(* Logix 5000 AddOnInstructionDefinition export Banner_TLF100_Param_v4; software revision 32.00; part 2 of 2 *)
(* tags used below, declared in another part *)
   TLF100 : Banner_TLF100_v2;
   Port_Data : Banner_IOL_Port_v4;
   Port : INT;   // Port Number that device is plugged into.
   Local_Control : DINT;
   Command_Being_Processed : BOOL;
   Update_Archive : BOOL;
   Index_Write_Inprocess : DINT;
   Index_Write_Control : DINT;
   Inprocess_Index : DINT;
   BS_Index : DINT;
   Index_W : DINT;
   W_Index : DINT;
   LT_Index2 : DINT;
   LT_Index1 : DINT;
(* Banner_TLF100_Param_v4, continued *)

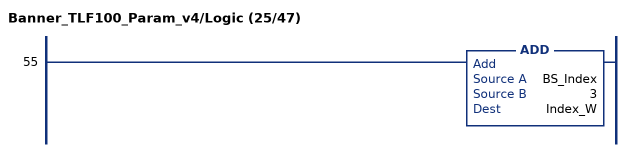
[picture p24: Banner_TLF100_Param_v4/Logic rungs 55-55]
   55: ADD(BS_Index,3,Index_W);
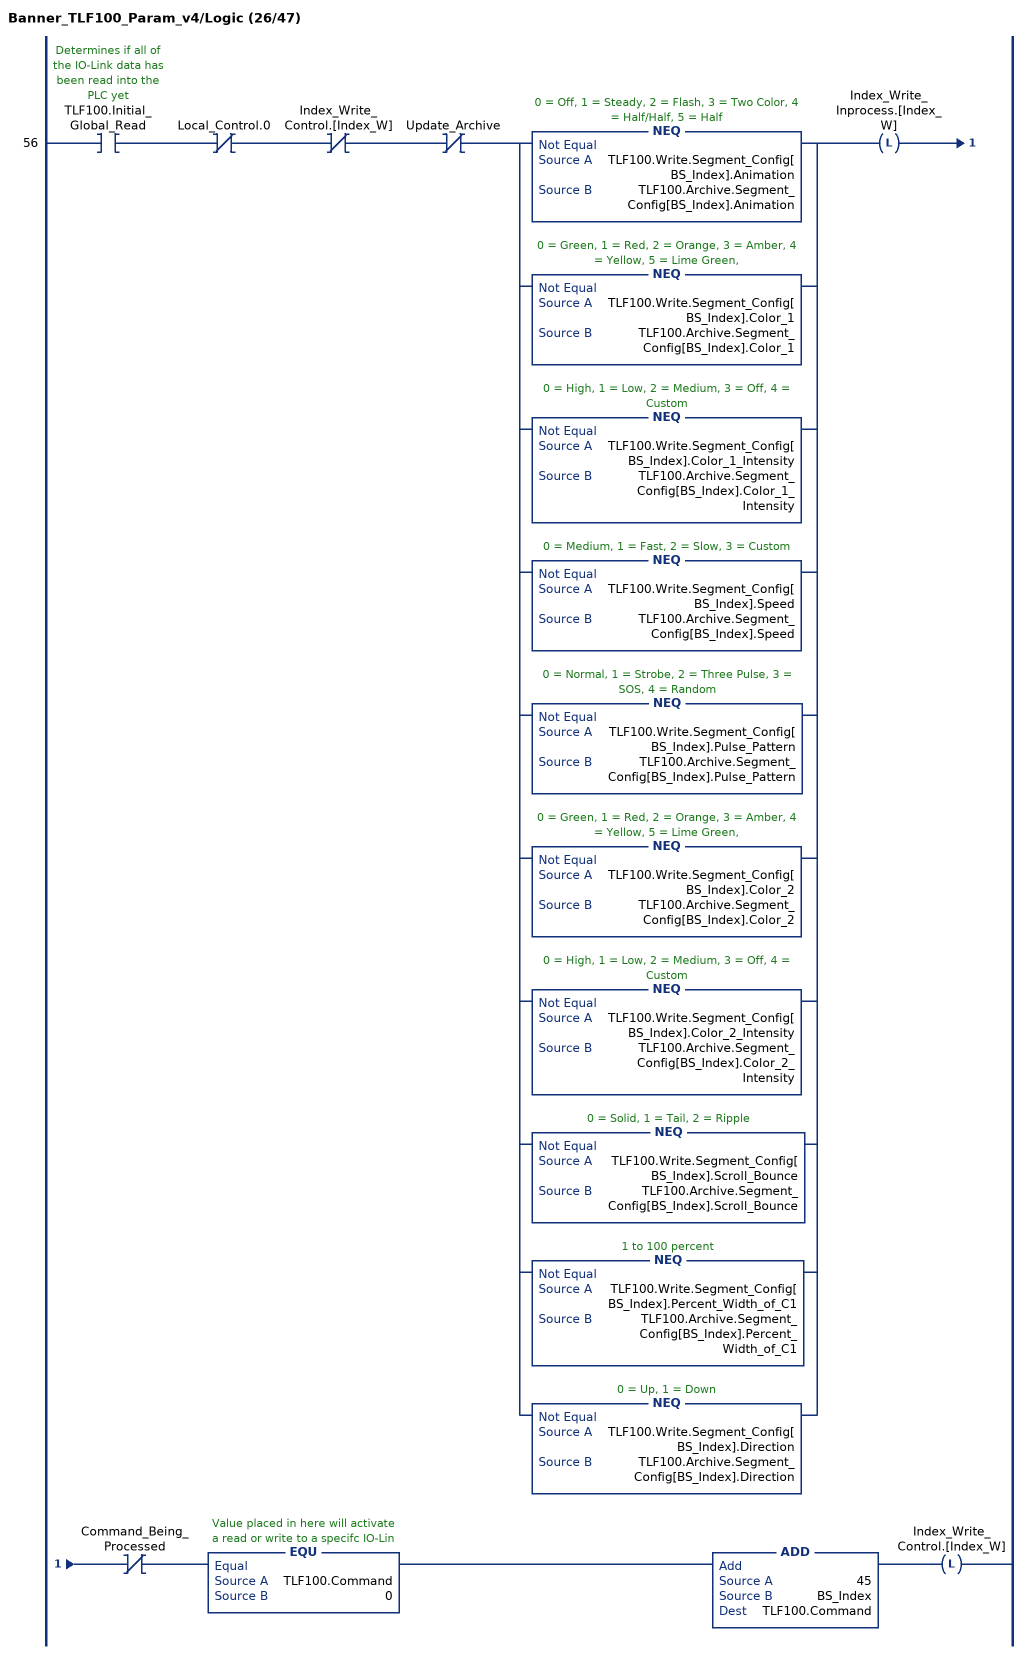
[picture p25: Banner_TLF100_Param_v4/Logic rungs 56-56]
   56: XIC(TLF100.Initial_Global_Read)XIO(Local_Control.0)XIO(Index_Write_Control.[Index_W])XIO(Update_Archive)[NEQ(TLF100.Write.Segment_Config[BS_Index].Animation,TLF100.Archive.Segment_Config[BS_Index].Animation) ,NEQ(TLF100.Write.Segment_Config[BS_Index].Color_1,TLF100.Archive.Segment_Config[BS_Index].Color_1) ,NEQ(TLF100.Write.Segment_Config[BS_Index].Color_1_Intensity,TLF100.Archive.Segment_Config[BS_Index].Color_1_Intensity) ,NEQ(TLF100.Write.Segment_Config[BS_Index].Speed,TLF100.Archive.Segment_Config[BS_Index].Speed) ,NEQ(TLF100.Write.Segment_Config[BS_Index].Pulse_Pattern,TLF100.Archive.Segment_Config[BS_Index].Pulse_Pattern) ,NEQ(TLF100.Write.Segment_Config[BS_Index].Color_2,TLF100.Archive.Segment_Config[BS_Index].Color_2) ,NEQ(TLF100.Write.Segment_Config[BS_Index].Color_2_Intensity,TLF100.Archive.Segment_Config[BS_Index].Color_2_Intensity) ,NEQ(TLF100.Write.Segment_Config[BS_Index].Scroll_Bounce,TLF100.Archive.Segment_Config[BS_Index].Scroll_Bounce) ,NEQ(TLF100.Write.Segment_Config[BS_Index].Percent_Width_of_C1,TLF100.Archive.Segment_Config[BS_Index].Percent_Width_of_C1) ,NEQ(TLF100.Write.Segment_Config[BS_Index].Direction,TLF100.Archive.Segment_Config[BS_Index].Direction) ]OTL(Index_Write_Inprocess.[Index_W])XIO(Command_Being_Processed)EQU(TLF100.Command,0)ADD(45,BS_Index,TLF100.Command)OTL(Index_Write_Control.[Index_W]);
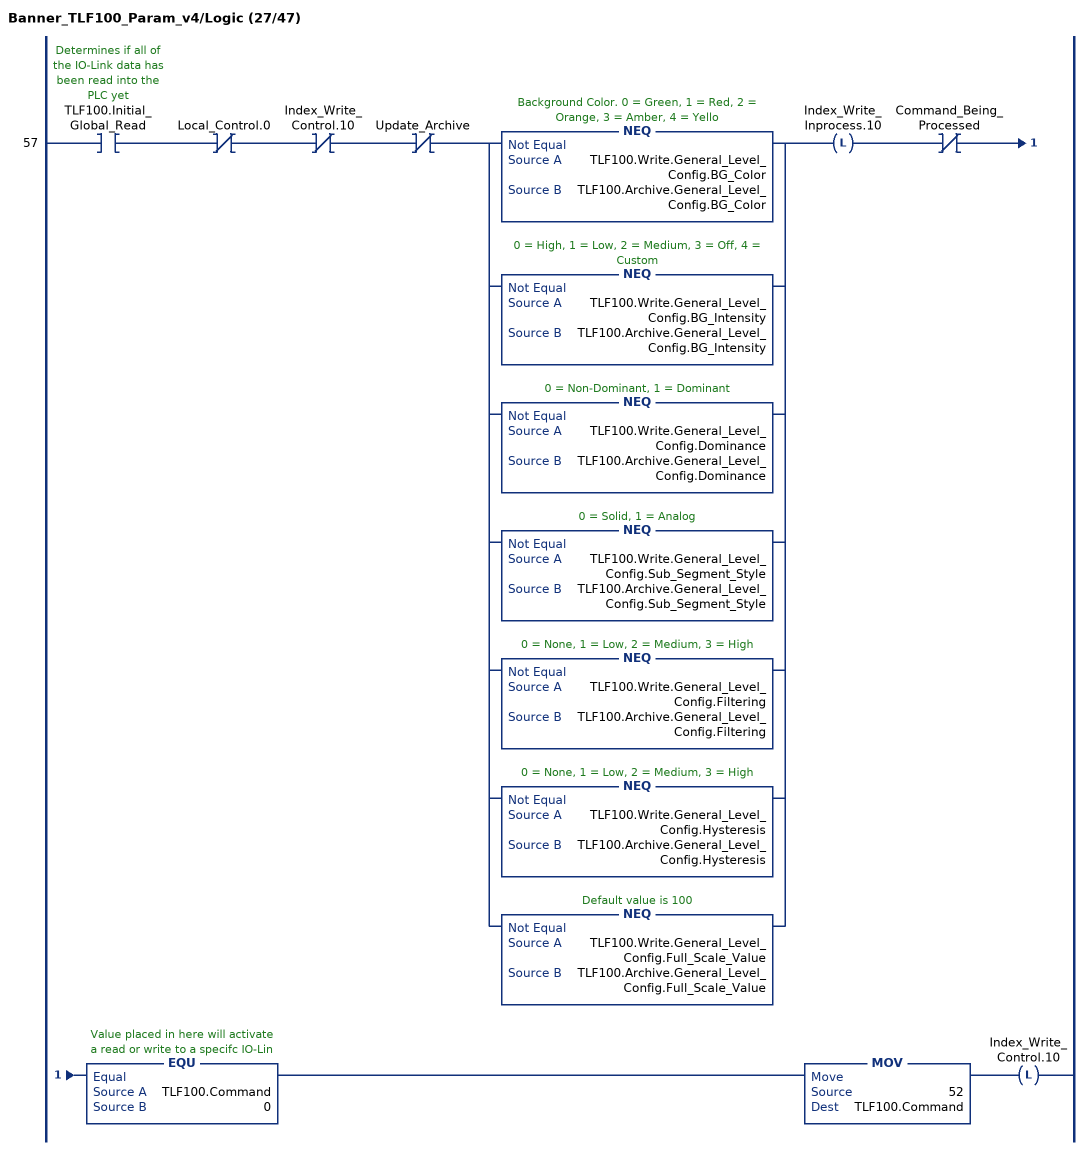
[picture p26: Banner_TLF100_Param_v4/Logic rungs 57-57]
   57: XIC(TLF100.Initial_Global_Read)XIO(Local_Control.0)XIO(Index_Write_Control.10)XIO(Update_Archive)[NEQ(TLF100.Write.General_Level_Config.BG_Color,TLF100.Archive.General_Level_Config.BG_Color) ,NEQ(TLF100.Write.General_Level_Config.BG_Intensity,TLF100.Archive.General_Level_Config.BG_Intensity) ,NEQ(TLF100.Write.General_Level_Config.Dominance,TLF100.Archive.General_Level_Config.Dominance) ,NEQ(TLF100.Write.General_Level_Config.Sub_Segment_Style,TLF100.Archive.General_Level_Config.Sub_Segment_Style) ,NEQ(TLF100.Write.General_Level_Config.Filtering,TLF100.Archive.General_Level_Config.Filtering) ,NEQ(TLF100.Write.General_Level_Config.Hysteresis,TLF100.Archive.General_Level_Config.Hysteresis) ,NEQ(TLF100.Write.General_Level_Config.Full_Scale_Value,TLF100.Archive.General_Level_Config.Full_Scale_Value) ]OTL(Index_Write_Inprocess.10)XIO(Command_Being_Processed)EQU(TLF100.Command,0)MOV(52,TLF100.Command)OTL(Index_Write_Control.10);
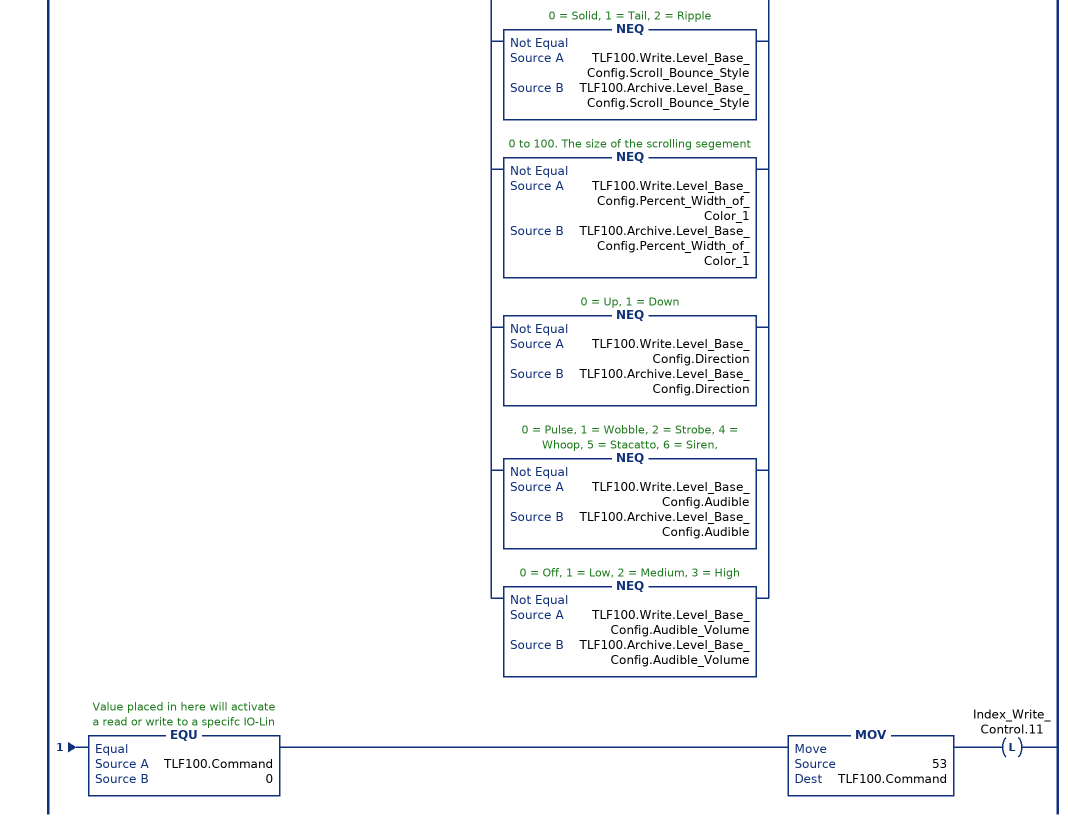
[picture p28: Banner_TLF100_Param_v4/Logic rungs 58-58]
   58: XIC(TLF100.Initial_Global_Read)XIO(Local_Control.0)XIO(Index_Write_Control.11)XIO(Update_Archive)[NEQ(TLF100.Write.Level_Base_Config.Animation,TLF100.Archive.Level_Base_Config.Animation) ,NEQ(TLF100.Write.Level_Base_Config.Color_1,TLF100.Archive.Level_Base_Config.Color_1) ,NEQ(TLF100.Write.Level_Base_Config.Color_1_Intensity,TLF100.Archive.Level_Base_Config.Color_1_Intensity) ,NEQ(TLF100.Write.Level_Base_Config.Speed,TLF100.Archive.Level_Base_Config.Speed) ,NEQ(TLF100.Write.Level_Base_Config.Pulse_Pattern,TLF100.Archive.Level_Base_Config.Pulse_Pattern) ,NEQ(TLF100.Write.Level_Base_Config.Color_2,TLF100.Archive.Level_Base_Config.Color_2) ,NEQ(TLF100.Write.Level_Base_Config.Color_2_Intensity,TLF100.Archive.Level_Base_Config.Color_2_Intensity) ,NEQ(TLF100.Write.Level_Base_Config.Scroll_Bounce_Style,TLF100.Archive.Level_Base_Config.Scroll_Bounce_Style) ,NEQ(TLF100.Write.Level_Base_Config.Percent_Width_of_Color_1,TLF100.Archive.Level_Base_Config.Percent_Width_of_Color_1) ,NEQ(TLF100.Write.Level_Base_Config.Direction,TLF100.Archive.Level_Base_Config.Direction) ,NEQ(TLF100.Write.Level_Base_Config.Audible,TLF100.Archive.Level_Base_Config.Audible) ,NEQ(TLF100.Write.Level_Base_Config.Audible_Volume,TLF100.Archive.Level_Base_Config.Audible_Volume) ]OTL(Index_Write_Inprocess.11)XIO(Command_Being_Processed)EQU(TLF100.Command,0)MOV(53,TLF100.Command)OTL(Index_Write_Control.11);
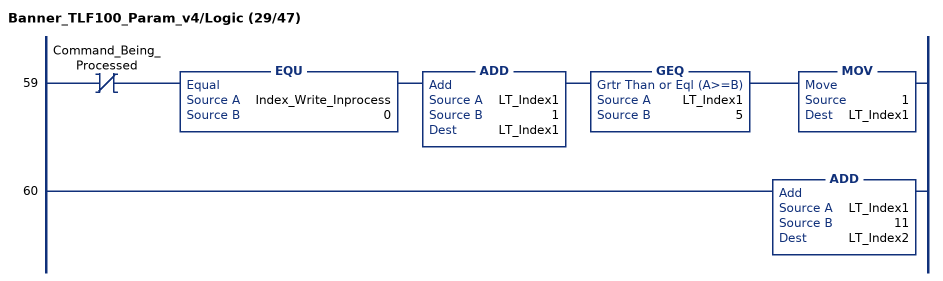
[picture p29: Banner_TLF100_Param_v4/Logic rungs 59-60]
   59: XIO(Command_Being_Processed)EQU(Index_Write_Inprocess,0)ADD(LT_Index1,1,LT_Index1)GEQ(LT_Index1,5)MOV(1,LT_Index1);
   60: ADD(LT_Index1,11,LT_Index2);
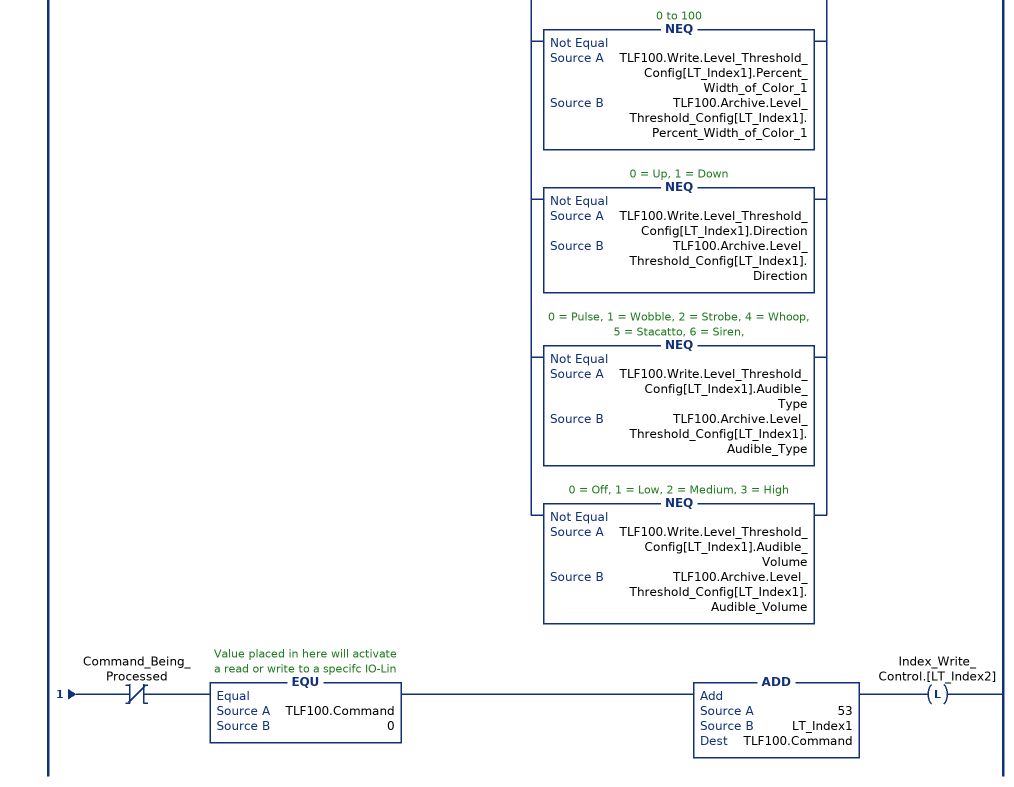
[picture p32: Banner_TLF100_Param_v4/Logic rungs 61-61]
   61: XIC(TLF100.Initial_Global_Read)XIO(Local_Control.0)XIO(Index_Write_Control.[LT_Index2])XIO(Update_Archive)[NEQ(TLF100.Write.Level_Threshold_Config[LT_Index1].Threshold_Enable,TLF100.Archive.Level_Threshold_Config[LT_Index1].Threshold_Enable) ,NEQ(TLF100.Write.Level_Threshold_Config[LT_Index1].Threshold_Value_Percent,TLF100.Archive.Level_Threshold_Config[LT_Index1].Threshold_Value_Percent) ,NEQ(TLF100.Write.Level_Threshold_Config[LT_Index1].Threshold_Comparison,TLF100.Archive.Level_Threshold_Config[LT_Index1].Threshold_Comparison) ,NEQ(TLF100.Write.Level_Threshold_Config[LT_Index1].Threshold_Override,TLF100.Archive.Level_Threshold_Config[LT_Index1].Threshold_Override) ,NEQ(TLF100.Write.Level_Threshold_Config[LT_Index1].Animation,TLF100.Archive.Level_Threshold_Config[LT_Index1].Animation) ,NEQ(TLF100.Write.Level_Threshold_Config[LT_Index1].Color_1,TLF100.Archive.Level_Threshold_Config[LT_Index1].Color_1) ,NEQ(TLF100.Write.Level_Threshold_Config[LT_Index1].Color_1_Intensity,TLF100.Archive.Level_Threshold_Config[LT_Index1].Color_1_Intensity) ,NEQ(TLF100.Write.Level_Threshold_Config[LT_Index1].Speed,TLF100.Archive.Level_Threshold_Config[LT_Index1].Speed) ,NEQ(TLF100.Write.Level_Threshold_Config[LT_Index1].Pulse_Pattern,TLF100.Archive.Level_Threshold_Config[LT_Index1].Pulse_Pattern) ,NEQ(TLF100.Write.Level_Threshold_Config[LT_Index1].Color_2,TLF100.Archive.Level_Threshold_Config[LT_Index1].Color_2) ,NEQ(TLF100.Write.Level_Threshold_Config[LT_Index1].Color_2_Intensity,TLF100.Archive.Level_Threshold_Config[LT_Index1].Color_2_Intensity) ,NEQ(TLF100.Write.Level_Threshold_Config[LT_Index1].Scroll_Bounce_Style,TLF100.Archive.Level_Threshold_Config[LT_Index1].Scroll_Bounce_Style) ,NEQ(TLF100.Write.Level_Threshold_Config[LT_Index1].Percent_Width_of_Color_1,TLF100.Archive.Level_Threshold_Config[LT_Index1].Percent_Width_of_Color_1) ,NEQ(TLF100.Write.Level_Threshold_Config[LT_Index1].Direction,TLF100.Archive.Level_Threshold_Config[LT_Index1].Direction) ,NEQ(TLF100.Write.Level_Threshold_Config[LT_Index1].Audible_Type,TLF100.Archive.Level_Threshold_Config[LT_Index1].Audible_Type) ,NEQ(TLF100.Write.Level_Threshold_Config[LT_Index1].Audible_Volume,TLF100.Archive.Level_Threshold_Config[LT_Index1].Audible_Volume) ]OTL(Index_Write_Inprocess.[LT_Index2])XIO(Command_Being_Processed)EQU(TLF100.Command,0)ADD(53,LT_Index1,TLF100.Command)OTL(Index_Write_Control.[LT_Index2]);
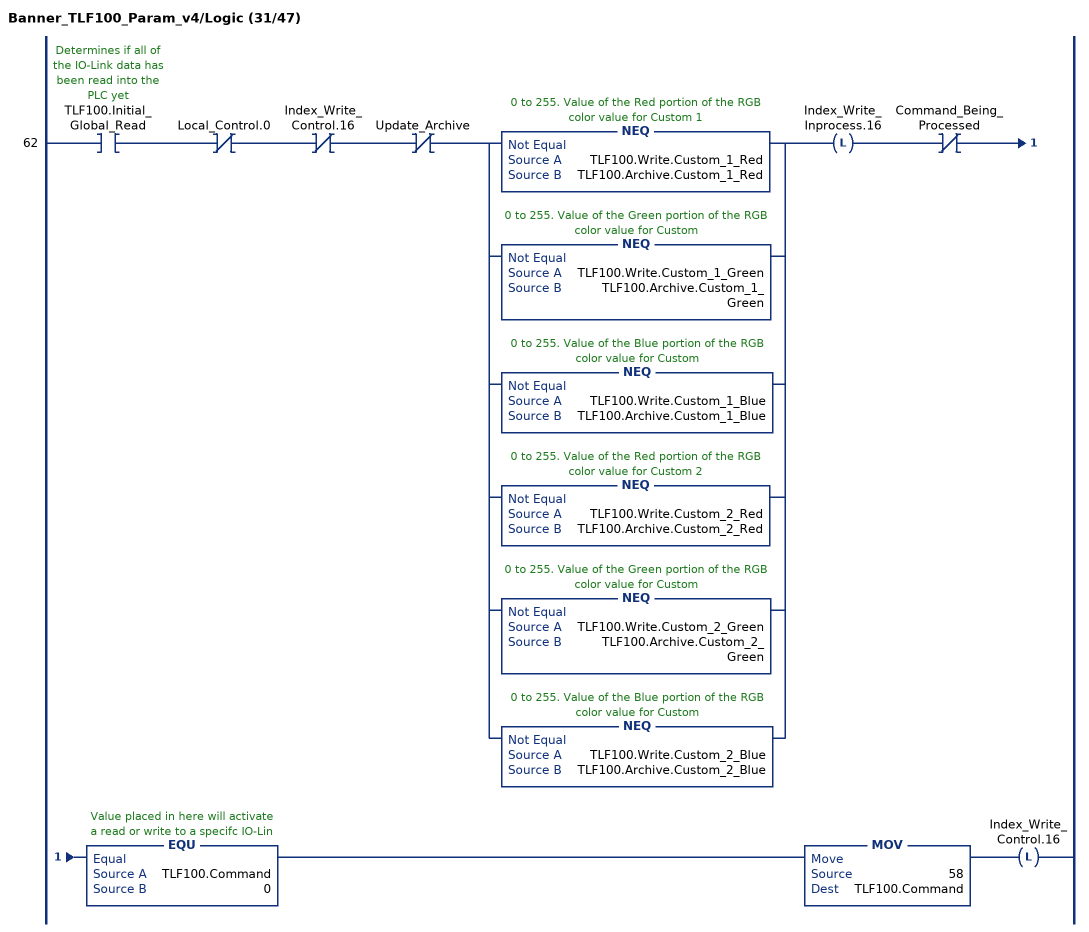
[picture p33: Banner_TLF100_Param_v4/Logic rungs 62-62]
   62: XIC(TLF100.Initial_Global_Read)XIO(Local_Control.0)XIO(Index_Write_Control.16)XIO(Update_Archive)[NEQ(TLF100.Write.Custom_1_Red,TLF100.Archive.Custom_1_Red) ,NEQ(TLF100.Write.Custom_1_Green,TLF100.Archive.Custom_1_Green) ,NEQ(TLF100.Write.Custom_1_Blue,TLF100.Archive.Custom_1_Blue) ,NEQ(TLF100.Write.Custom_2_Red,TLF100.Archive.Custom_2_Red) ,NEQ(TLF100.Write.Custom_2_Green,TLF100.Archive.Custom_2_Green) ,NEQ(TLF100.Write.Custom_2_Blue,TLF100.Archive.Custom_2_Blue) ]OTL(Index_Write_Inprocess.16)XIO(Command_Being_Processed)EQU(TLF100.Command,0)MOV(58,TLF100.Command)OTL(Index_Write_Control.16);
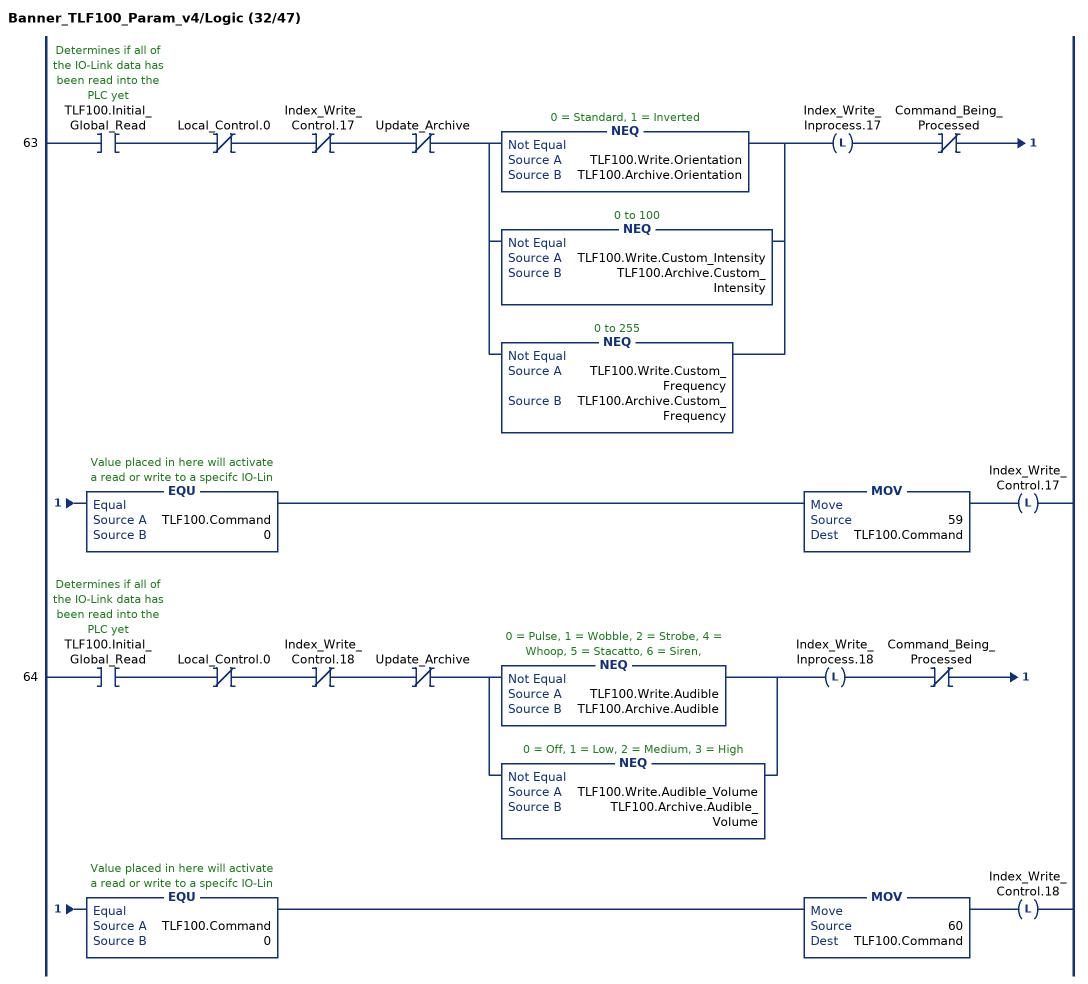
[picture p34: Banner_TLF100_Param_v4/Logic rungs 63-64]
   63: XIC(TLF100.Initial_Global_Read)XIO(Local_Control.0)XIO(Index_Write_Control.17)XIO(Update_Archive)[NEQ(TLF100.Write.Orientation,TLF100.Archive.Orientation) ,NEQ(TLF100.Write.Custom_Intensity,TLF100.Archive.Custom_Intensity) ,NEQ(TLF100.Write.Custom_Frequency,TLF100.Archive.Custom_Frequency) ]OTL(Index_Write_Inprocess.17)XIO(Command_Being_Processed)EQU(TLF100.Command,0)MOV(59,TLF100.Command)OTL(Index_Write_Control.17);
   64: XIC(TLF100.Initial_Global_Read)XIO(Local_Control.0)XIO(Index_Write_Control.18)XIO(Update_Archive)[NEQ(TLF100.Write.Audible,TLF100.Archive.Audible) ,NEQ(TLF100.Write.Audible_Volume,TLF100.Archive.Audible_Volume) ]OTL(Index_Write_Inprocess.18)XIO(Command_Being_Processed)EQU(TLF100.Command,0)MOV(60,TLF100.Command)OTL(Index_Write_Control.18);
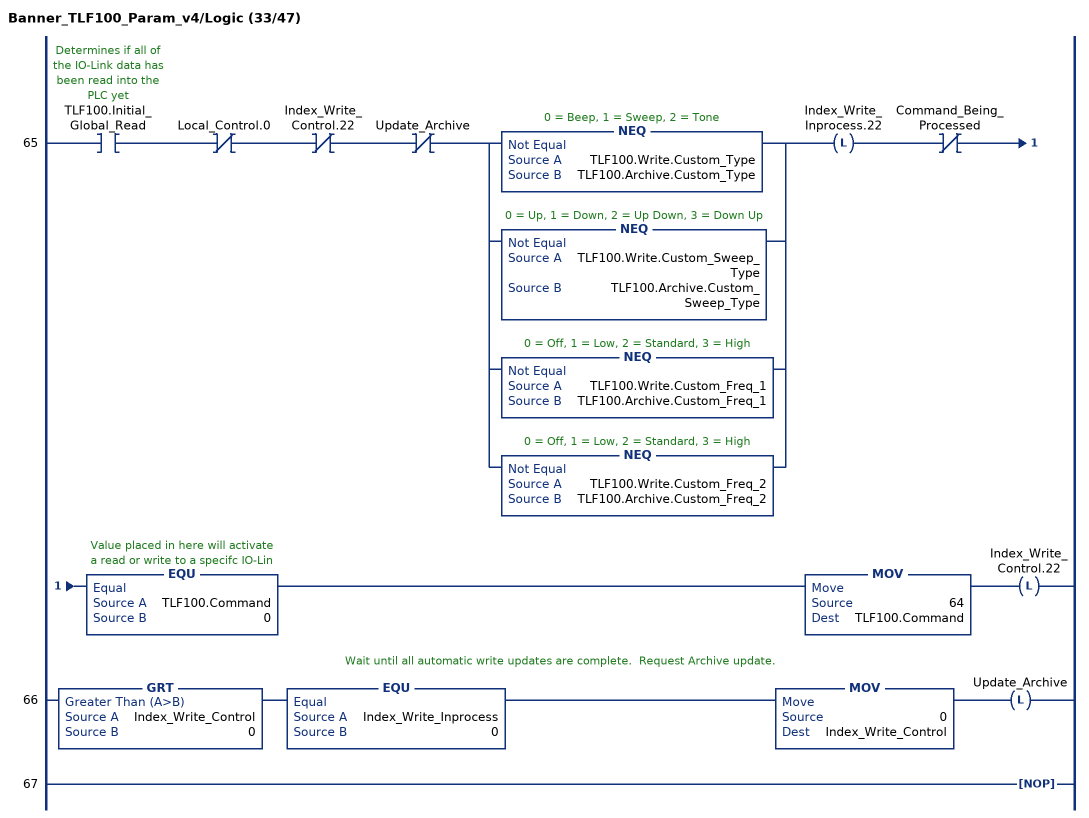
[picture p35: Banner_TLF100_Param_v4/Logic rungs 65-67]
   65: XIC(TLF100.Initial_Global_Read)XIO(Local_Control.0)XIO(Index_Write_Control.22)XIO(Update_Archive)[NEQ(TLF100.Write.Custom_Type,TLF100.Archive.Custom_Type) ,NEQ(TLF100.Write.Custom_Sweep_Type,TLF100.Archive.Custom_Sweep_Type) ,NEQ(TLF100.Write.Custom_Freq_1,TLF100.Archive.Custom_Freq_1) ,NEQ(TLF100.Write.Custom_Freq_2,TLF100.Archive.Custom_Freq_2) ]OTL(Index_Write_Inprocess.22)XIO(Command_Being_Processed)EQU(TLF100.Command,0)MOV(64,TLF100.Command)OTL(Index_Write_Control.22);
   // Wait until all automatic write updates are complete.  Request Archive update.
   66: GRT(Index_Write_Control,0)EQU(Index_Write_Inprocess,0)MOV(0,Index_Write_Control)OTL(Update_Archive);
   67: NOP();
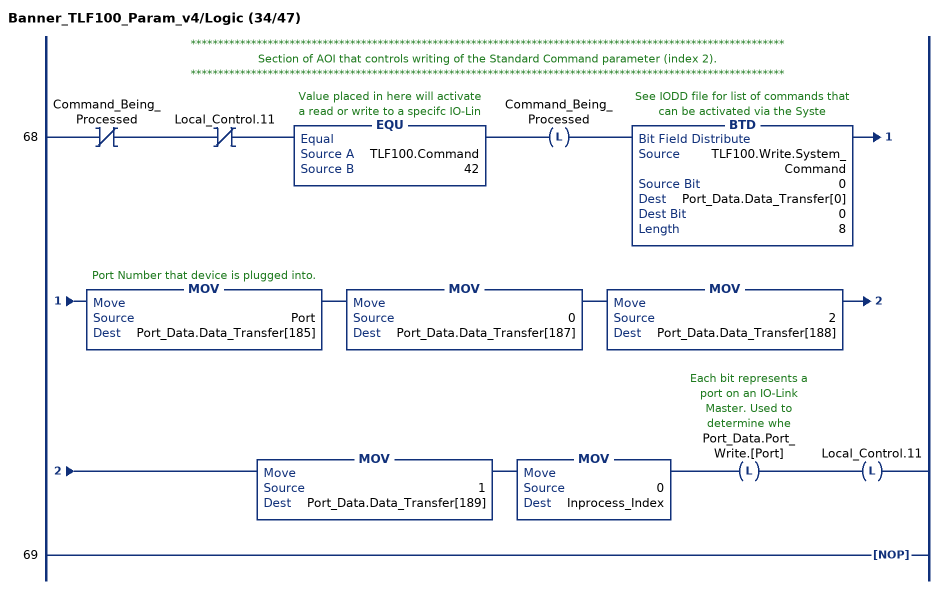
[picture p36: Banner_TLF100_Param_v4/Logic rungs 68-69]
   // ************************************************************************************************************
   // Section of AOI that controls writing of the Standard Command parameter (index 2).
   // ************************************************************************************************************
   68: XIO(Command_Being_Processed)XIO(Local_Control.11)EQU(TLF100.Command,42)OTL(Command_Being_Processed)BTD(TLF100.Write.System_Command,0,Port_Data.Data_Transfer[0],0,8)MOV(Port,Port_Data.Data_Transfer[185])MOV(0,Port_Data.Data_Transfer[187])MOV(2,Port_Data.Data_Transfer[188])MOV(1,Port_Data.Data_Transfer[189])MOV(0,Inprocess_Index)OTL(Port_Data.Port_Write.[Port])OTL(Local_Control.11);
   69: NOP();
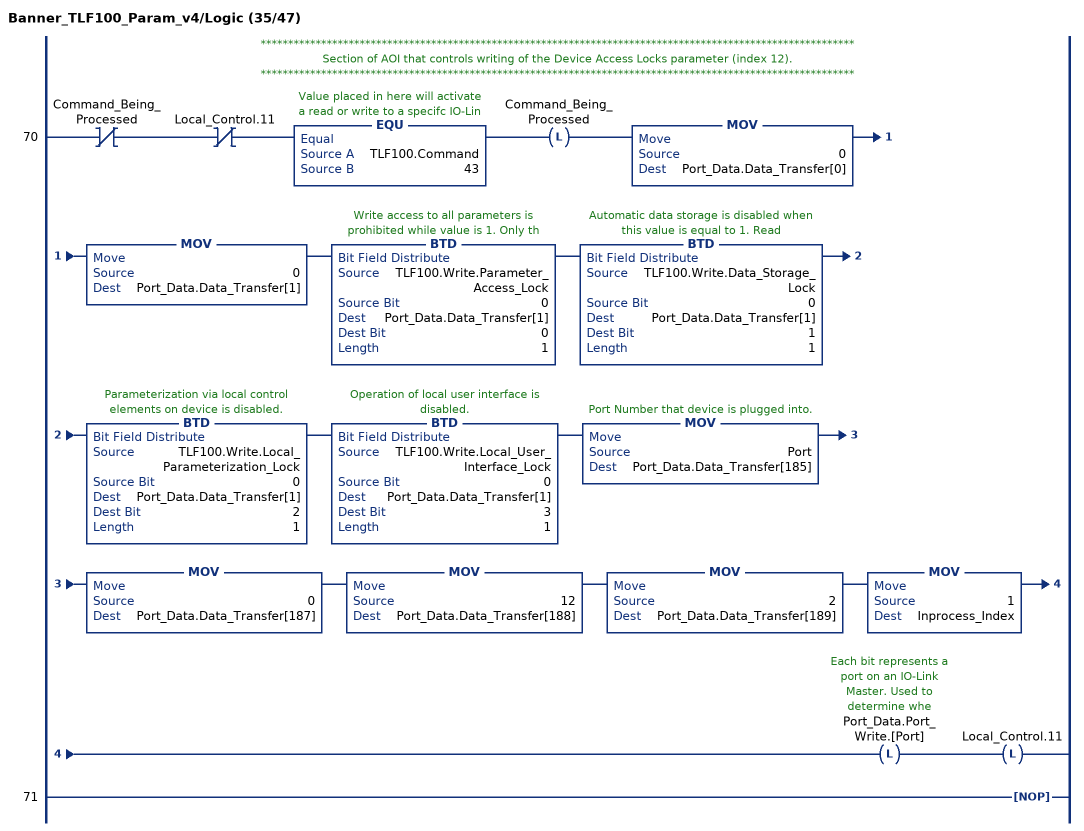
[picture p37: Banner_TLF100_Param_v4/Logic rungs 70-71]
   // ************************************************************************************************************
   // Section of AOI that controls writing of the Device Access Locks parameter (index 12).
   // ************************************************************************************************************
   70: XIO(Command_Being_Processed)XIO(Local_Control.11)EQU(TLF100.Command,43)OTL(Command_Being_Processed)MOV(0,Port_Data.Data_Transfer[0])MOV(0,Port_Data.Data_Transfer[1])BTD(TLF100.Write.Parameter_Access_Lock,0,Port_Data.Data_Transfer[1],0,1)BTD(TLF100.Write.Data_Storage_Lock,0,Port_Data.Data_Transfer[1],1,1)BTD(TLF100.Write.Local_Parameterization_Lock,0,Port_Data.Data_Transfer[1],2,1)BTD(TLF100.Write.Local_User_Interface_Lock,0,Port_Data.Data_Transfer[1],3,1)MOV(Port,Port_Data.Data_Transfer[185])MOV(0,Port_Data.Data_Transfer[187])MOV(12,Port_Data.Data_Transfer[188])MOV(2,Port_Data.Data_Transfer[189])MOV(1,Inprocess_Index)OTL(Port_Data.Port_Write.[Port])OTL(Local_Control.11);
   71: NOP();
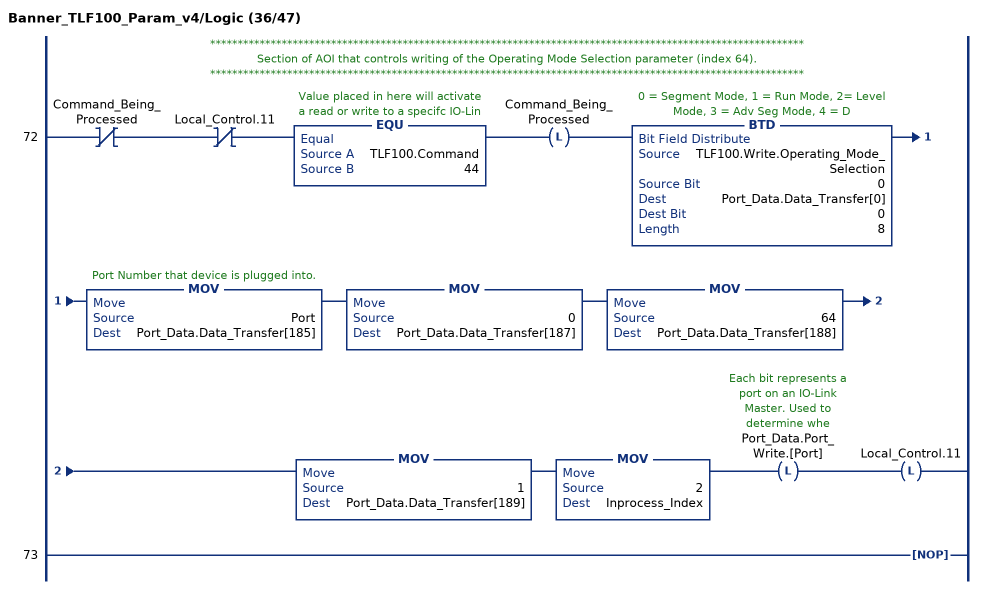
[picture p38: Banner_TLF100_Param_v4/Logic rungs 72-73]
   // ************************************************************************************************************
   // Section of AOI that controls writing of the Operating Mode Selection parameter (index 64).
   // ************************************************************************************************************
   72: XIO(Command_Being_Processed)XIO(Local_Control.11)EQU(TLF100.Command,44)OTL(Command_Being_Processed)BTD(TLF100.Write.Operating_Mode_Selection,0,Port_Data.Data_Transfer[0],0,8)MOV(Port,Port_Data.Data_Transfer[185])MOV(0,Port_Data.Data_Transfer[187])MOV(64,Port_Data.Data_Transfer[188])MOV(1,Port_Data.Data_Transfer[189])MOV(2,Inprocess_Index)OTL(Port_Data.Port_Write.[Port])OTL(Local_Control.11);
   73: NOP();
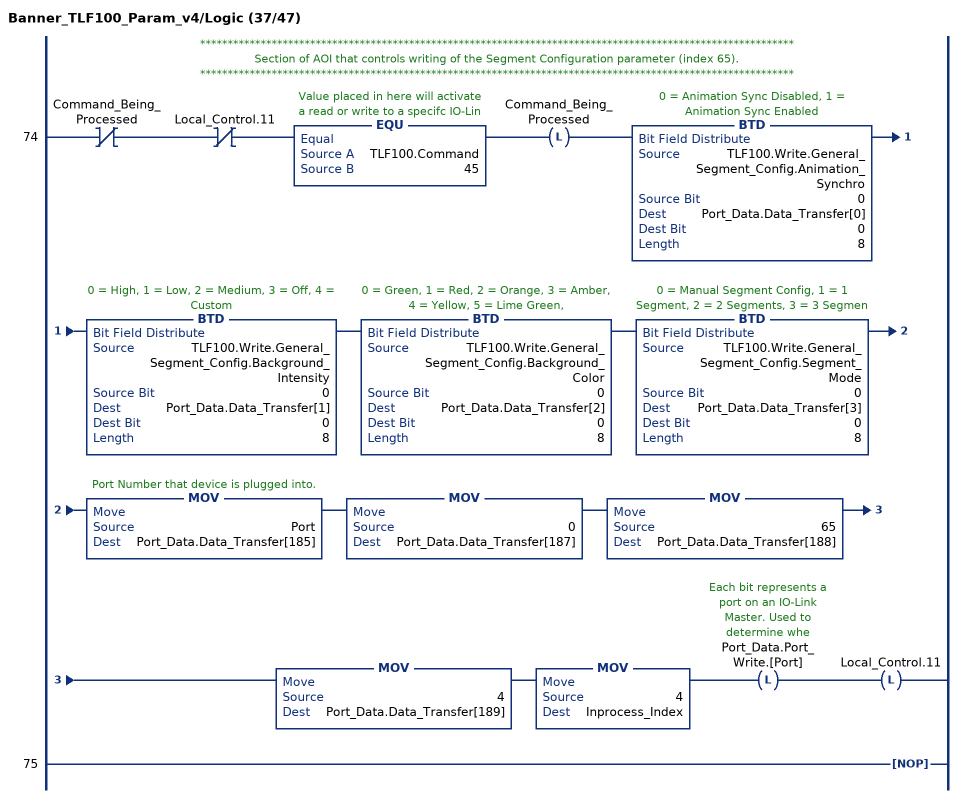
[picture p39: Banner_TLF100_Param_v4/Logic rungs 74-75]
   // ************************************************************************************************************
   // Section of AOI that controls writing of the Segment Configuration parameter (index 65).
   // ************************************************************************************************************
   74: XIO(Command_Being_Processed)XIO(Local_Control.11)EQU(TLF100.Command,45)OTL(Command_Being_Processed)BTD(TLF100.Write.General_Segment_Config.Animation_Synchro,0,Port_Data.Data_Transfer[0],0,8)BTD(TLF100.Write.General_Segment_Config.Background_Intensity,0,Port_Data.Data_Transfer[1],0,8)BTD(TLF100.Write.General_Segment_Config.Background_Color,0,Port_Data.Data_Transfer[2],0,8)BTD(TLF100.Write.General_Segment_Config.Segment_Mode,0,Port_Data.Data_Transfer[3],0,8)MOV(Port,Port_Data.Data_Transfer[185])MOV(0,Port_Data.Data_Transfer[187])MOV(65,Port_Data.Data_Transfer[188])MOV(4,Port_Data.Data_Transfer[189])MOV(4,Inprocess_Index)OTL(Port_Data.Port_Write.[Port])OTL(Local_Control.11);
   75: NOP();
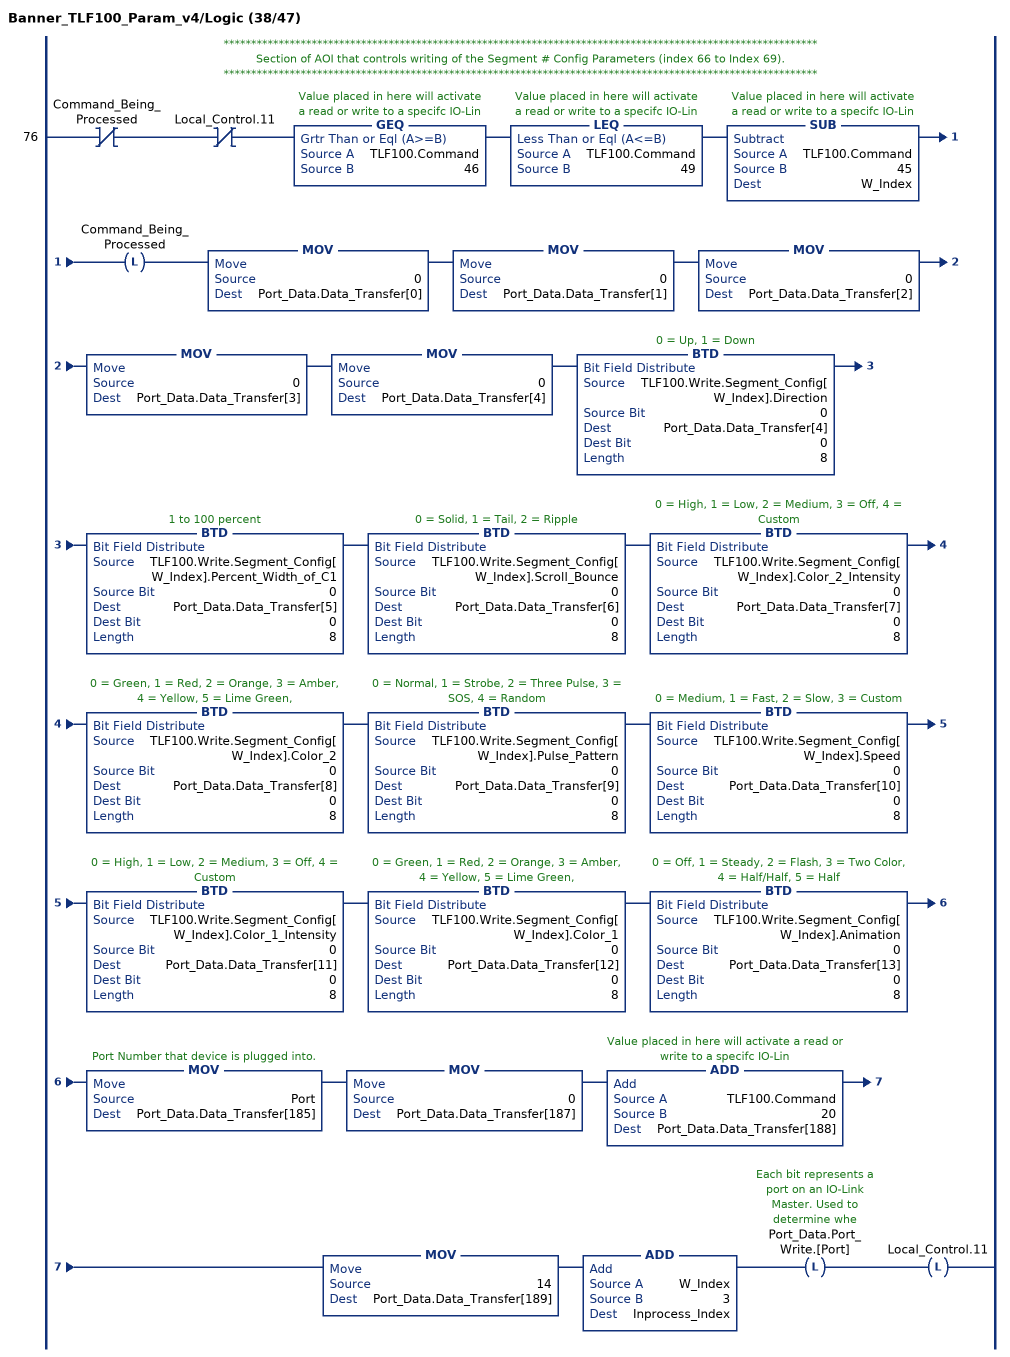
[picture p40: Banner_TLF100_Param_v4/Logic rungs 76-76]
   // ************************************************************************************************************
   // Section of AOI that controls writing of the Segment # Config Parameters (index 66 to Index 69).
   // ************************************************************************************************************
   76: XIO(Command_Being_Processed)XIO(Local_Control.11)GEQ(TLF100.Command,46)LEQ(TLF100.Command,49)SUB(TLF100.Command,45,W_Index)OTL(Command_Being_Processed)MOV(0,Port_Data.Data_Transfer[0])MOV(0,Port_Data.Data_Transfer[1])MOV(0,Port_Data.Data_Transfer[2])MOV(0,Port_Data.Data_Transfer[3])MOV(0,Port_Data.Data_Transfer[4])BTD(TLF100.Write.Segment_Config[W_Index].Direction,0,Port_Data.Data_Transfer[4],0,8)BTD(TLF100.Write.Segment_Config[W_Index].Percent_Width_of_C1,0,Port_Data.Data_Transfer[5],0,8)BTD(TLF100.Write.Segment_Config[W_Index].Scroll_Bounce,0,Port_Data.Data_Transfer[6],0,8)BTD(TLF100.Write.Segment_Config[W_Index].Color_2_Intensity,0,Port_Data.Data_Transfer[7],0,8)BTD(TLF100.Write.Segment_Config[W_Index].Color_2,0,Port_Data.Data_Transfer[8],0,8)BTD(TLF100.Write.Segment_Config[W_Index].Pulse_Pattern,0,Port_Data.Data_Transfer[9],0,8)BTD(TLF100.Write.Segment_Config[W_Index].Speed,0,Port_Data.Data_Transfer[10],0,8)BTD(TLF100.Write.Segment_Config[W_Index].Color_1_Intensity,0,Port_Data.Data_Transfer[11],0,8)BTD(TLF100.Write.Segment_Config[W_Index].Color_1,0,Port_Data.Data_Transfer[12],0,8)BTD(TLF100.Write.Segment_Config[W_Index].Animation,0,Port_Data.Data_Transfer[13],0,8)MOV(Port,Port_Data.Data_Transfer[185])MOV(0,Port_Data.Data_Transfer[187])ADD(TLF100.Command,20,Port_Data.Data_Transfer[188])MOV(14,Port_Data.Data_Transfer[189])ADD(W_Index,3,Inprocess_Index)OTL(Port_Data.Port_Write.[Port])OTL(Local_Control.11);
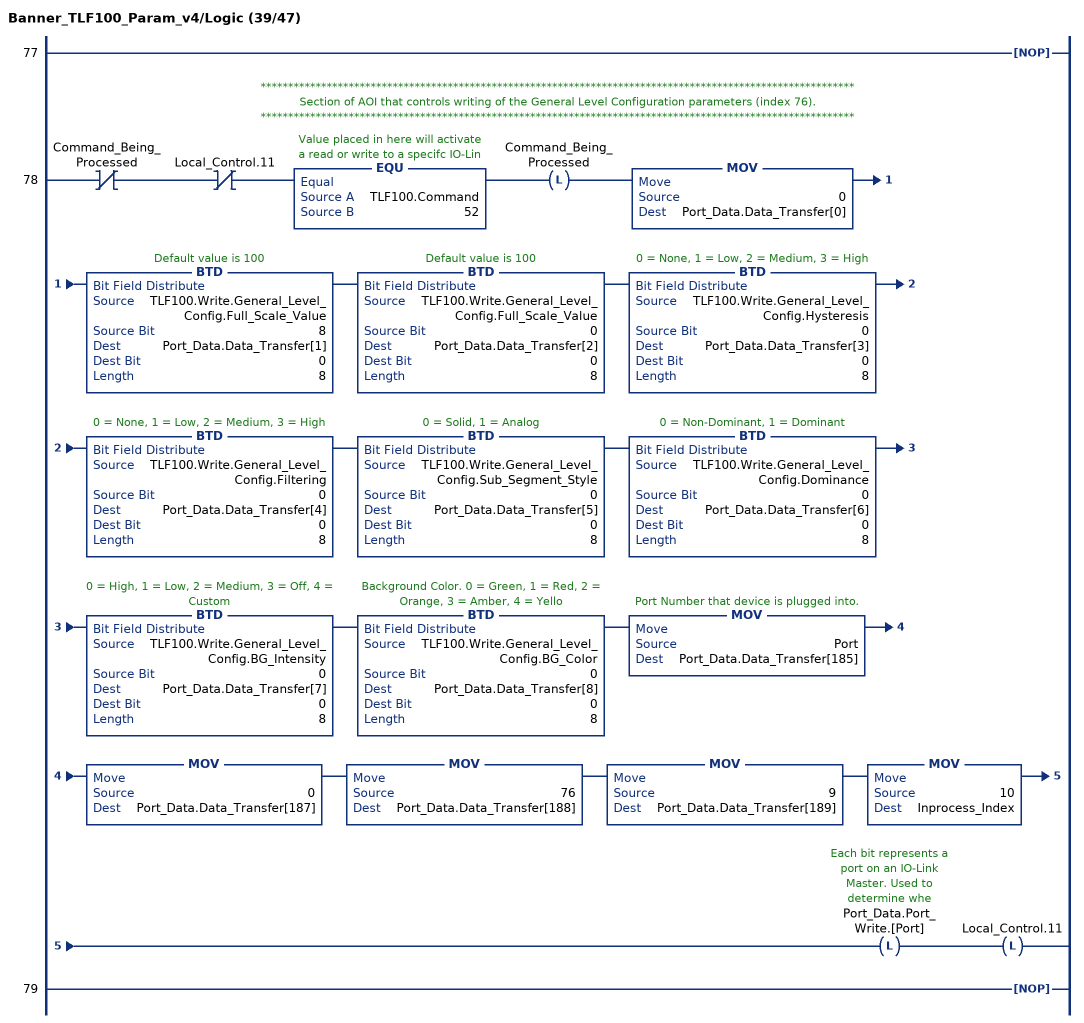
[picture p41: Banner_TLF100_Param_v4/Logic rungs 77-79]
   77: NOP();
   // ************************************************************************************************************
   // Section of AOI that controls writing of the General Level Configuration parameters (index 76).
   // ************************************************************************************************************
   78: XIO(Command_Being_Processed)XIO(Local_Control.11)EQU(TLF100.Command,52)OTL(Command_Being_Processed)MOV(0,Port_Data.Data_Transfer[0])BTD(TLF100.Write.General_Level_Config.Full_Scale_Value,8,Port_Data.Data_Transfer[1],0,8)BTD(TLF100.Write.General_Level_Config.Full_Scale_Value,0,Port_Data.Data_Transfer[2],0,8)BTD(TLF100.Write.General_Level_Config.Hysteresis,0,Port_Data.Data_Transfer[3],0,8)BTD(TLF100.Write.General_Level_Config.Filtering,0,Port_Data.Data_Transfer[4],0,8)BTD(TLF100.Write.General_Level_Config.Sub_Segment_Style,0,Port_Data.Data_Transfer[5],0,8)BTD(TLF100.Write.General_Level_Config.Dominance,0,Port_Data.Data_Transfer[6],0,8)BTD(TLF100.Write.General_Level_Config.BG_Intensity,0,Port_Data.Data_Transfer[7],0,8)BTD(TLF100.Write.General_Level_Config.BG_Color,0,Port_Data.Data_Transfer[8],0,8)MOV(Port,Port_Data.Data_Transfer[185])MOV(0,Port_Data.Data_Transfer[187])MOV(76,Port_Data.Data_Transfer[188])MOV(9,Port_Data.Data_Transfer[189])MOV(10,Inprocess_Index)OTL(Port_Data.Port_Write.[Port])OTL(Local_Control.11);
   79: NOP();
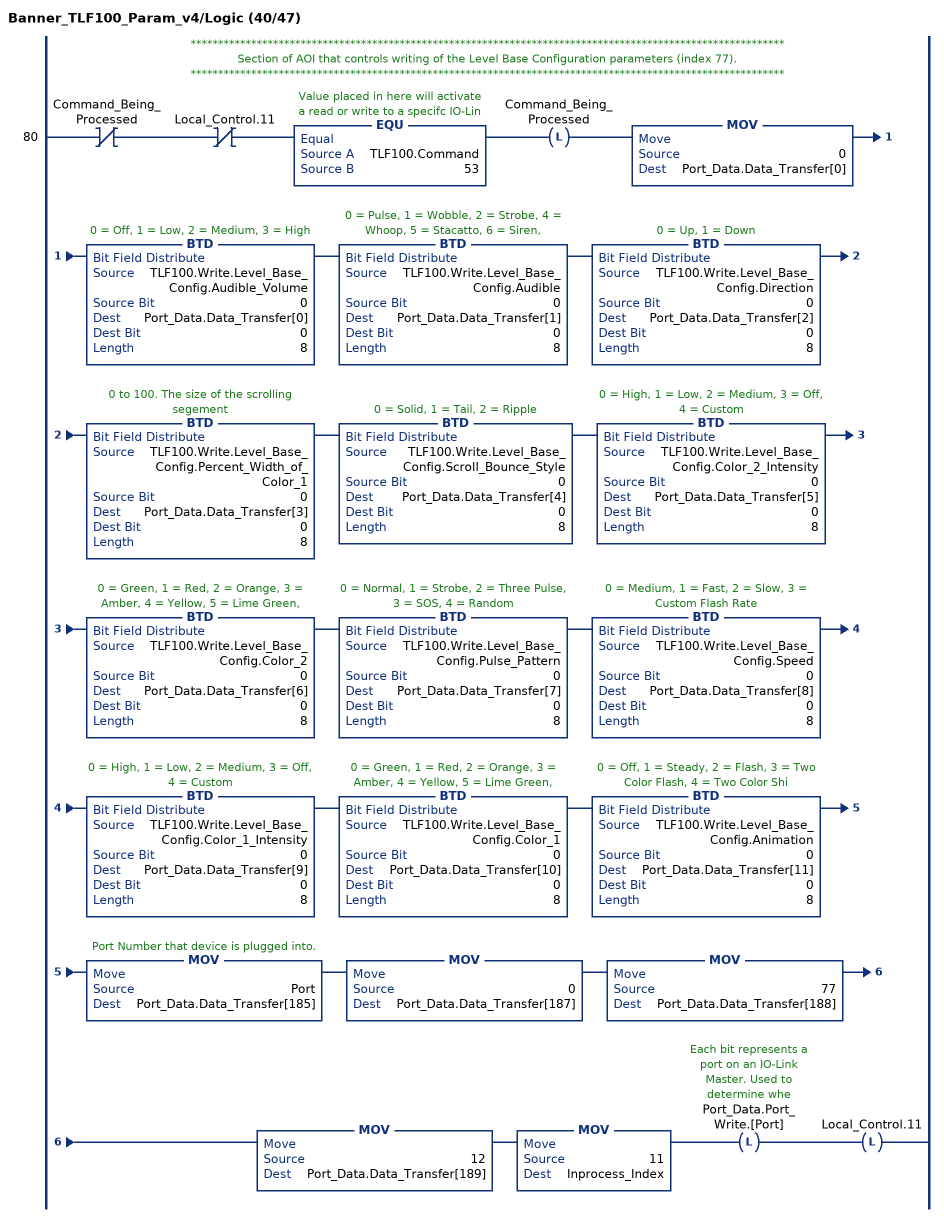
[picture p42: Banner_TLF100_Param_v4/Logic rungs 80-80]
   // ************************************************************************************************************
   // Section of AOI that controls writing of the Level Base Configuration parameters (index 77).
   // ************************************************************************************************************
   80: XIO(Command_Being_Processed)XIO(Local_Control.11)EQU(TLF100.Command,53)OTL(Command_Being_Processed)MOV(0,Port_Data.Data_Transfer[0])BTD(TLF100.Write.Level_Base_Config.Audible_Volume,0,Port_Data.Data_Transfer[0],0,8)BTD(TLF100.Write.Level_Base_Config.Audible,0,Port_Data.Data_Transfer[1],0,8)BTD(TLF100.Write.Level_Base_Config.Direction,0,Port_Data.Data_Transfer[2],0,8)BTD(TLF100.Write.Level_Base_Config.Percent_Width_of_Color_1,0,Port_Data.Data_Transfer[3],0,8)BTD(TLF100.Write.Level_Base_Config.Scroll_Bounce_Style,0,Port_Data.Data_Transfer[4],0,8)BTD(TLF100.Write.Level_Base_Config.Color_2_Intensity,0,Port_Data.Data_Transfer[5],0,8)BTD(TLF100.Write.Level_Base_Config.Color_2,0,Port_Data.Data_Transfer[6],0,8)BTD(TLF100.Write.Level_Base_Config.Pulse_Pattern,0,Port_Data.Data_Transfer[7],0,8)BTD(TLF100.Write.Level_Base_Config.Speed,0,Port_Data.Data_Transfer[8],0,8)BTD(TLF100.Write.Level_Base_Config.Color_1_Intensity,0,Port_Data.Data_Transfer[9],0,8)BTD(TLF100.Write.Level_Base_Config.Color_1,0,Port_Data.Data_Transfer[10],0,8)BTD(TLF100.Write.Level_Base_Config.Animation,0,Port_Data.Data_Transfer[11],0,8)MOV(Port,Port_Data.Data_Transfer[185])MOV(0,Port_Data.Data_Transfer[187])MOV(77,Port_Data.Data_Transfer[188])MOV(12,Port_Data.Data_Transfer[189])MOV(11,Inprocess_Index)OTL(Port_Data.Port_Write.[Port])OTL(Local_Control.11);
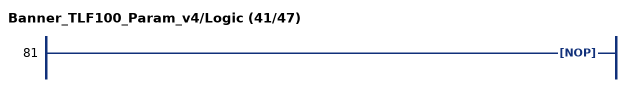
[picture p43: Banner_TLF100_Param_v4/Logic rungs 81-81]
   81: NOP();
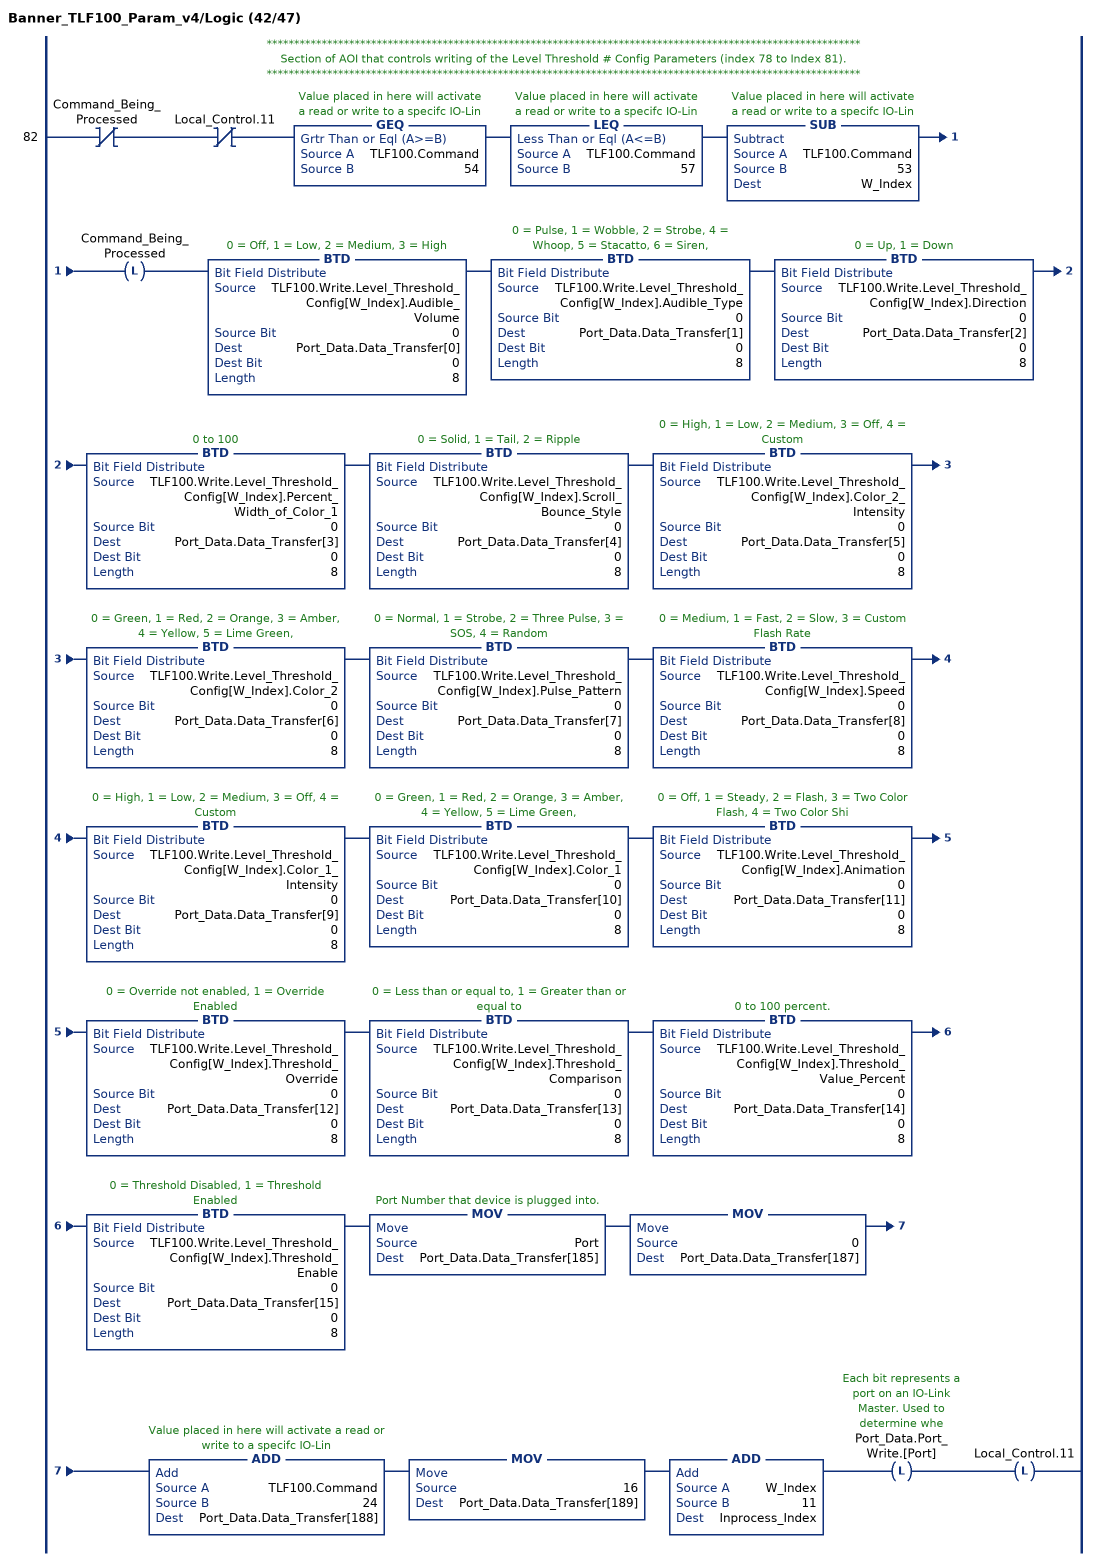
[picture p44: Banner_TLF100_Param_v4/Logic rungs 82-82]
   // ************************************************************************************************************
   // Section of AOI that controls writing of the Level Threshold # Config Parameters (index 78 to Index 81).
   // ************************************************************************************************************
   82: XIO(Command_Being_Processed)XIO(Local_Control.11)GEQ(TLF100.Command,54)LEQ(TLF100.Command,57)SUB(TLF100.Command,53,W_Index)OTL(Command_Being_Processed)BTD(TLF100.Write.Level_Threshold_Config[W_Index].Audible_Volume,0,Port_Data.Data_Transfer[0],0,8)BTD(TLF100.Write.Level_Threshold_Config[W_Index].Audible_Type,0,Port_Data.Data_Transfer[1],0,8)BTD(TLF100.Write.Level_Threshold_Config[W_Index].Direction,0,Port_Data.Data_Transfer[2],0,8)BTD(TLF100.Write.Level_Threshold_Config[W_Index].Percent_Width_of_Color_1,0,Port_Data.Data_Transfer[3],0,8)BTD(TLF100.Write.Level_Threshold_Config[W_Index].Scroll_Bounce_Style,0,Port_Data.Data_Transfer[4],0,8)BTD(TLF100.Write.Level_Threshold_Config[W_Index].Color_2_Intensity,0,Port_Data.Data_Transfer[5],0,8)BTD(TLF100.Write.Level_Threshold_Config[W_Index].Color_2,0,Port_Data.Data_Transfer[6],0,8)BTD(TLF100.Write.Level_Threshold_Config[W_Index].Pulse_Pattern,0,Port_Data.Data_Transfer[7],0,8)BTD(TLF100.Write.Level_Threshold_Config[W_Index].Speed,0,Port_Data.Data_Transfer[8],0,8)BTD(TLF100.Write.Level_Threshold_Config[W_Index].Color_1_Intensity,0,Port_Data.Data_Transfer[9],0,8)BTD(TLF100.Write.Level_Threshold_Config[W_Index].Color_1,0,Port_Data.Data_Transfer[10],0,8)BTD(TLF100.Write.Level_Threshold_Config[W_Index].Animation,0,Port_Data.Data_Transfer[11],0,8)BTD(TLF100.Write.Level_Threshold_Config[W_Index].Threshold_Override,0,Port_Data.Data_Transfer[12],0,8)BTD(TLF100.Write.Level_Threshold_Config[W_Index].Threshold_Comparison,0,Port_Data.Data_Transfer[13],0,8)BTD(TLF100.Write.Level_Threshold_Config[W_Index].Threshold_Value_Percent,0,Port_Data.Data_Transfer[14],0,8)BTD(TLF100.Write.Level_Threshold_Config[W_Index].Threshold_Enable,0,Port_Data.Data_Transfer[15],0,8)MOV(Port,Port_Data.Data_Transfer[185])MOV(0,Port_Data.Data_Transfer[187])ADD(TLF100.Command,24,Port_Data.Data_Transfer[188])MOV(16,Port_Data.Data_Transfer[189])ADD(W_Index,11,Inprocess_Index)OTL(Port_Data.Port_Write.[Port])OTL(Local_Control.11);
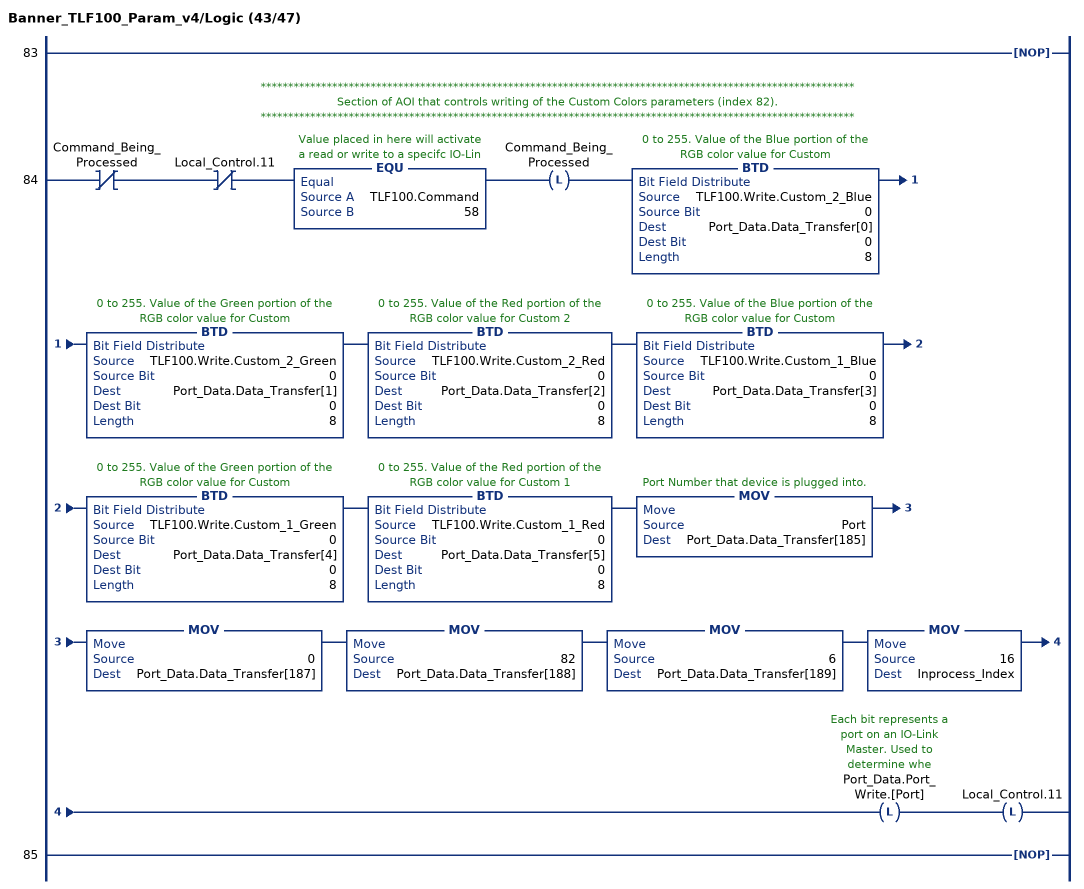
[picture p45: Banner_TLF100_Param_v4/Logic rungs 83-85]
   83: NOP();
   // ************************************************************************************************************
   // Section of AOI that controls writing of the Custom Colors parameters (index 82).
   // ************************************************************************************************************
   84: XIO(Command_Being_Processed)XIO(Local_Control.11)EQU(TLF100.Command,58)OTL(Command_Being_Processed)BTD(TLF100.Write.Custom_2_Blue,0,Port_Data.Data_Transfer[0],0,8)BTD(TLF100.Write.Custom_2_Green,0,Port_Data.Data_Transfer[1],0,8)BTD(TLF100.Write.Custom_2_Red,0,Port_Data.Data_Transfer[2],0,8)BTD(TLF100.Write.Custom_1_Blue,0,Port_Data.Data_Transfer[3],0,8)BTD(TLF100.Write.Custom_1_Green,0,Port_Data.Data_Transfer[4],0,8)BTD(TLF100.Write.Custom_1_Red,0,Port_Data.Data_Transfer[5],0,8)MOV(Port,Port_Data.Data_Transfer[185])MOV(0,Port_Data.Data_Transfer[187])MOV(82,Port_Data.Data_Transfer[188])MOV(6,Port_Data.Data_Transfer[189])MOV(16,Inprocess_Index)OTL(Port_Data.Port_Write.[Port])OTL(Local_Control.11);
   85: NOP();
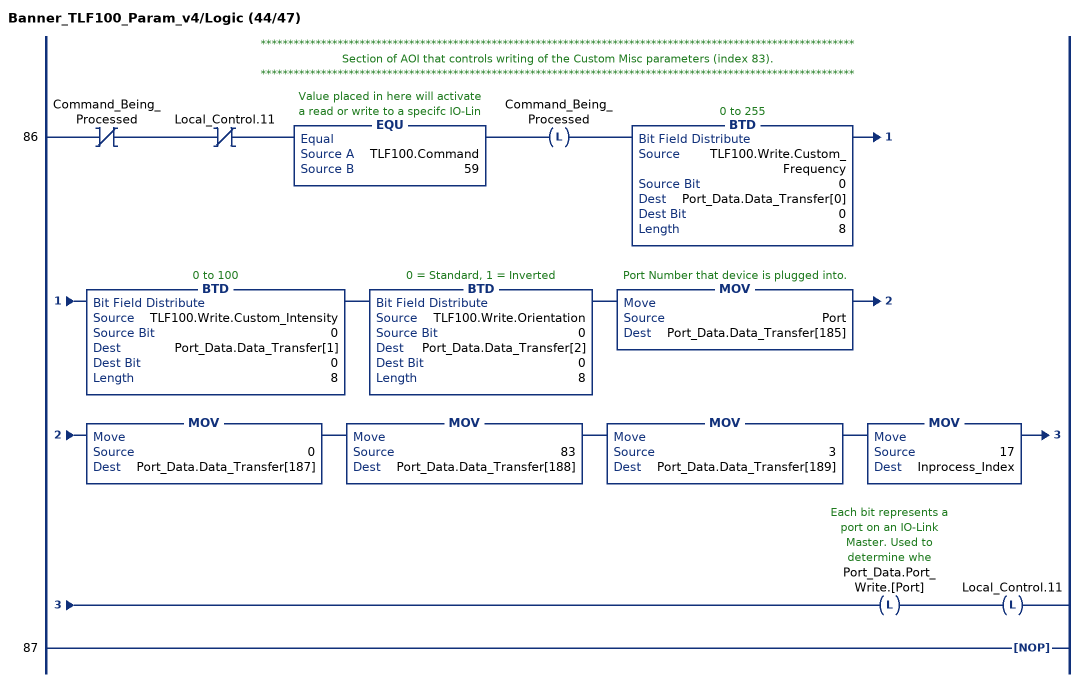
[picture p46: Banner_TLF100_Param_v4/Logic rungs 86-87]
   // ************************************************************************************************************
   // Section of AOI that controls writing of the Custom Misc parameters (index 83).
   // ************************************************************************************************************
   86: XIO(Command_Being_Processed)XIO(Local_Control.11)EQU(TLF100.Command,59)OTL(Command_Being_Processed)BTD(TLF100.Write.Custom_Frequency,0,Port_Data.Data_Transfer[0],0,8)BTD(TLF100.Write.Custom_Intensity,0,Port_Data.Data_Transfer[1],0,8)BTD(TLF100.Write.Orientation,0,Port_Data.Data_Transfer[2],0,8)MOV(Port,Port_Data.Data_Transfer[185])MOV(0,Port_Data.Data_Transfer[187])MOV(83,Port_Data.Data_Transfer[188])MOV(3,Port_Data.Data_Transfer[189])MOV(17,Inprocess_Index)OTL(Port_Data.Port_Write.[Port])OTL(Local_Control.11);
   87: NOP();
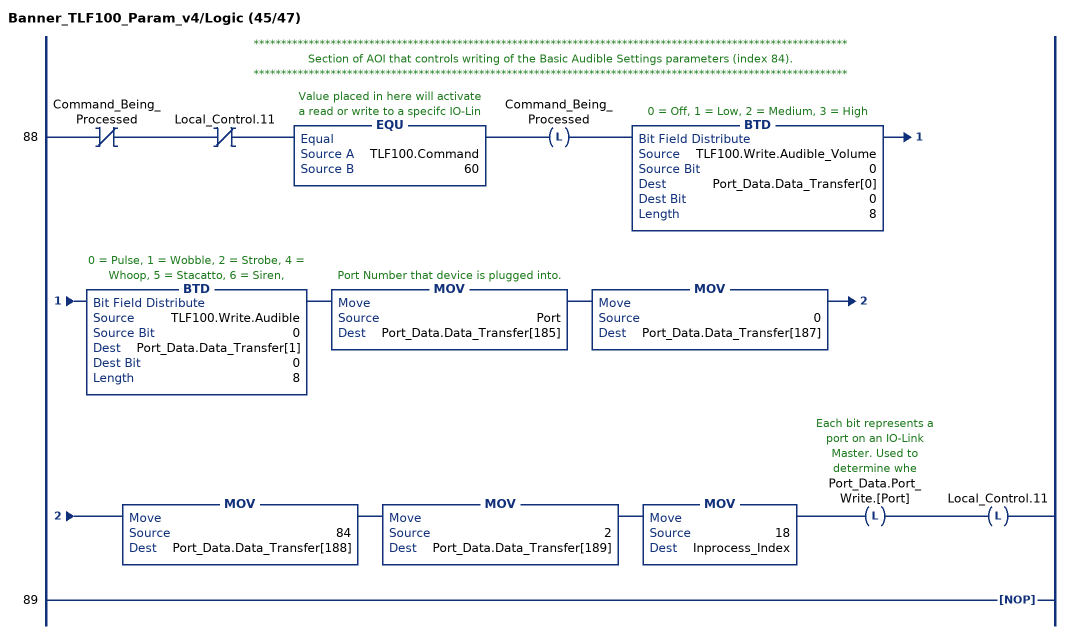
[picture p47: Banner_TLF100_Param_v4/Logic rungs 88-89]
   // ************************************************************************************************************
   // Section of AOI that controls writing of the Basic Audible Settings parameters (index 84).
   // ************************************************************************************************************
   88: XIO(Command_Being_Processed)XIO(Local_Control.11)EQU(TLF100.Command,60)OTL(Command_Being_Processed)BTD(TLF100.Write.Audible_Volume,0,Port_Data.Data_Transfer[0],0,8)BTD(TLF100.Write.Audible,0,Port_Data.Data_Transfer[1],0,8)MOV(Port,Port_Data.Data_Transfer[185])MOV(0,Port_Data.Data_Transfer[187])MOV(84,Port_Data.Data_Transfer[188])MOV(2,Port_Data.Data_Transfer[189])MOV(18,Inprocess_Index)OTL(Port_Data.Port_Write.[Port])OTL(Local_Control.11);
   89: NOP();
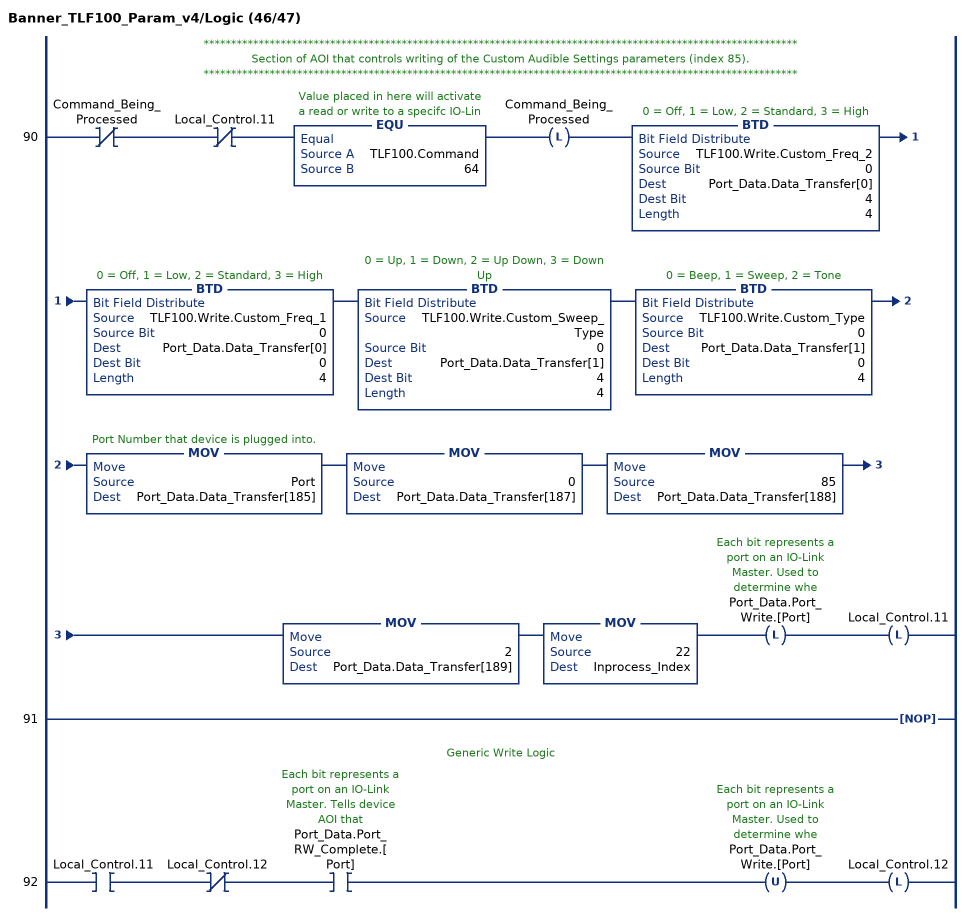
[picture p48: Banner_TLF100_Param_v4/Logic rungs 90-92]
   // ************************************************************************************************************
   // Section of AOI that controls writing of the Custom Audible Settings parameters (index 85).
   // ************************************************************************************************************
   90: XIO(Command_Being_Processed)XIO(Local_Control.11)EQU(TLF100.Command,64)OTL(Command_Being_Processed)BTD(TLF100.Write.Custom_Freq_2,0,Port_Data.Data_Transfer[0],4,4)BTD(TLF100.Write.Custom_Freq_1,0,Port_Data.Data_Transfer[0],0,4)BTD(TLF100.Write.Custom_Sweep_Type,0,Port_Data.Data_Transfer[1],4,4)BTD(TLF100.Write.Custom_Type,0,Port_Data.Data_Transfer[1],0,4)MOV(Port,Port_Data.Data_Transfer[185])MOV(0,Port_Data.Data_Transfer[187])MOV(85,Port_Data.Data_Transfer[188])MOV(2,Port_Data.Data_Transfer[189])MOV(22,Inprocess_Index)OTL(Port_Data.Port_Write.[Port])OTL(Local_Control.11);
   91: NOP();
   // Generic Write Logic
   92: XIC(Local_Control.11)XIO(Local_Control.12)XIC(Port_Data.Port_RW_Complete.[Port])OTU(Port_Data.Port_Write.[Port])OTL(Local_Control.12);
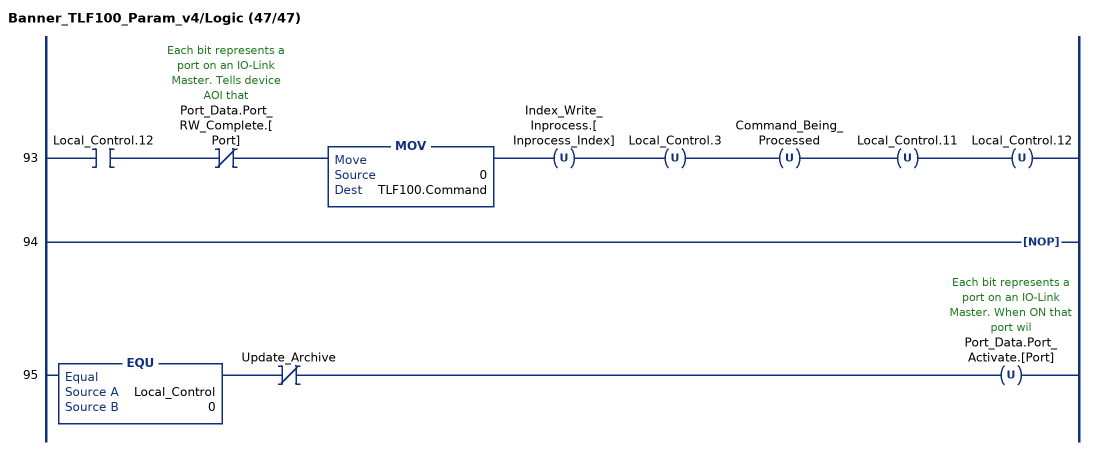
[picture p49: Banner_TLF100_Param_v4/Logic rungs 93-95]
   93: XIC(Local_Control.12)XIO(Port_Data.Port_RW_Complete.[Port])MOV(0,TLF100.Command)OTU(Index_Write_Inprocess.[Inprocess_Index])OTU(Local_Control.3)OTU(Command_Being_Processed)OTU(Local_Control.11)OTU(Local_Control.12);
   94: NOP();
   95: EQU(Local_Control,0)XIO(Update_Archive)OTU(Port_Data.Port_Activate.[Port]);
END_ROUTINE
END_ADD_ON_INSTRUCTION
